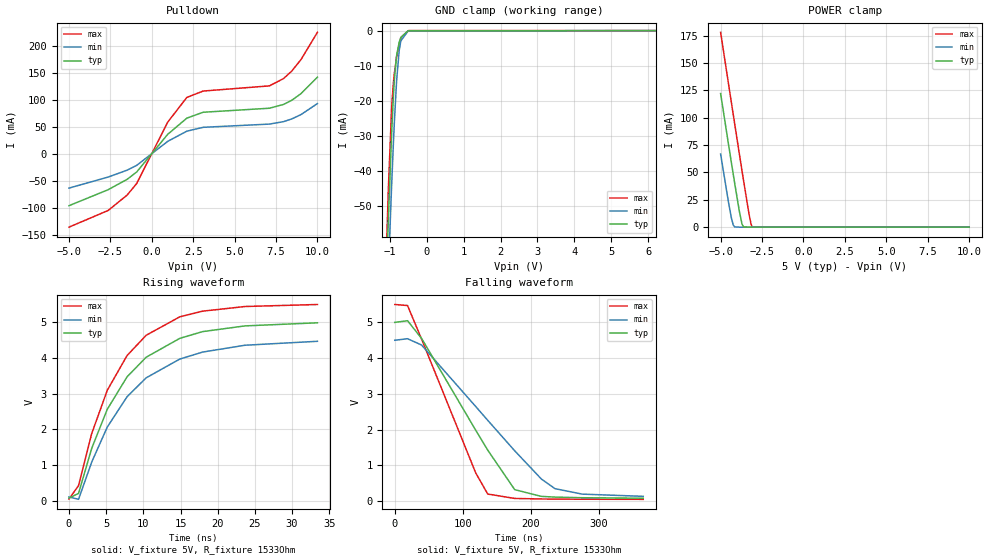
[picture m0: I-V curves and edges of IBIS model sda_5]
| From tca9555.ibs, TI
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|   sda_5 Model
[Model]   sda_5
Model_type   I/O_open_drain
Polarity   Non-Inverting
Vinl = 1.5
Vinh = 3.5
Vmeas = 2.5
Vref = 5
Cref = 100pF
Rref = 1533
|   typ   min   max
|   (nom PVT)   (fast PVT)   (slow PVT)
C_comp   1.437e-12   1.340e-12   1.585e-12
[Model spec]
|subparameter
Vinl   1.5   1.35   1.65
Vinh   3.5   3.15   3.85
| Where nom  PVT is Nominal Process, 5V, 27C
|   Fast PVT is Strong Process,  5.5V, -40C
|   Slow PVT is Weak Process,   4.5V, 100C
[Voltage Range]   5   4.5   5.5
|Junction Temperature
[Temperature Range]   27   100   -40
[Pullup Reference]   5   4.5   5.5
[Pulldown Reference]   0   0   0
[Power Clamp Reference]   5   4.5   5.5
[GND Clamp Reference]   0   0   0
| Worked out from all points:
|   slope of the pulldown table from 0 to 0.75 V, typ, clamps not added: 26.3 ohm
|   GND clamp passes 1 mA (typ) near -0.60 V on its own axis
|   POWER clamp passes 1 mA (typ) near -3.66 V on its own axis
|   falling waveform, V_fixture 5V, R_fixture 1533Ohm: 20-80 % time 92.2ns typ, 121ns min, 69.4ns max; typ from 5 V to 0.086 V
|   rising waveform, V_fixture 5V, R_fixture 1533Ohm: 20-80 % time 7.83ns typ, 8.51ns min, 7.11ns max; typ from 0.078 V to 4.98 V
[Pulldown]
|   Voltage   I(typ)   I(min)   I(max)
-5V       -96.37mA   -63.77mA   -136.1mA
-2.635V   -66.76mA   -43.31mA   -105.2mA
-1.486V   -47.45mA   -30.49mA   -76.69mA
-913.5mV  -33.98mA   -21.71mA   -55.33mA
967.5mV   36.03mA    22.95mA    58.62mA
2.117V    65.81mA    41.68mA    104.2mA
3.1V      76.74mA    48.82mA    116mA
7.101V    84.21mA    54.81mA    125.6mA
7.958V    91.23mA    59.35mA    139.2mA
8.447V    98.85mA    64.3mA     152.9mA
9.004V    111.1mA    72.36mA    174.1mA
10V       141.8mA    92.78mA    224.8mA
[GND Clamp]
|   Voltage   I(typ)   I(min)   I(max)
-5V       -1.721A    -1.563A    -1.985A
-1.09V    -70.04mA   -83.89mA   -62.51mA
-1.04V    -54.67mA   -69.24mA   -46.02mA
-1.036V   -53.33mA   -67.95mA   -44.62mA
-946.5mV  -28.78mA   -43.47mA   -21.52mA
-900.5mV  -18.55mA   -31.97mA   -14.75mA
-875mV    -14.06mA   -26.1mA    -12.18mA
-815mV    -7.162mA   -14.38mA   -7.57mA
-743mV    -3.318mA   -5.569mA   -3.645mA
-699mV    -1.959mA   -2.92mA    -2.031mA
-500mV    -58.24uA   -113.1uA   -30.74uA
10V       0A         0A         0A
[POWER Clamp]
|   Voltage   I(typ)   I(min)   I(max)
-5V       122.2mA    66.83mA    178.2mA
-4.519V   75.31mA    22.22mA    130.6mA
-4.343V   58.41mA    7.966mA    113.4mA
-4.235V   48.11mA    1.854mA    102.8mA
-4.15V    40.09mA    219.4uA    94.43mA
-3.865V   14.26mA    48.32nA    66.64mA
-3.71V    2.889mA    13.86nA    51.65mA
-3.61V    172.9uA    12.73nA    42.06mA
-3.272V   0A         10.16nA    10.96mA
-3.163V   0A         0A         2.802mA
-3.091V   0A         0A         279.9uA
10V       0A         0A         0A
[Ramp]
R_load = 1533
|   typ   min   max
dV/dt_r   2.9531/7.93136e-09   2.63426/8.70584e-09   3.26856/7.14248e-09
dV/dt_f   2.95157/9.22988e-08   2.62862/1.2171e-07   3.26824/6.93898e-08
[Falling Waveform]
V_fixture = 5V
V_fixture_min = 4.5V
V_fixture_max = 5.5V
R_fixture = 1533Ohm
|   Time   V(typ)   V(min)   V(max)
0s        5V         4.5V       5.5V
18.76ns   5.047V     4.544V     5.471V
39.53ns   4.55V      4.366V     4.529V
119.1ns   1.987V     2.649V     793.4mV
136.8ns   1.43V      2.263V     202mV
176.5ns   324.8mV    1.411V     78.91mV
215.7ns   136.6mV    623.3mV    64.2mV
235.7ns   116.8mV    353.3mV    60.98mV
275.7ns   99.03mV    199.8mV    57.39mV
365.7ns   85.99mV    137.8mV    54.26mV
[Rising Waveform]
V_fixture = 5V
V_fixture_min = 4.5V
V_fixture_max = 5.5V
R_fixture = 1533Ohm
|   Time   V(typ)   V(min)   V(max)
0s        78.15mV    109.5mV    52.38mV
1.289ns   209.3mV    43.5mV     426.3mV
3.063ns   1.471V     1.086V     1.884V
5.155ns   2.562V     2.065V     3.094V
7.819ns   3.471V     2.914V     4.065V
10.38ns   4.017V     3.441V     4.631V
14.9ns    4.545V     3.966V     5.147V
17.98ns   4.734V     4.162V     5.306V
23.68ns   4.894V     4.353V     5.436V
33.41ns   4.98V      4.463V     5.492V
